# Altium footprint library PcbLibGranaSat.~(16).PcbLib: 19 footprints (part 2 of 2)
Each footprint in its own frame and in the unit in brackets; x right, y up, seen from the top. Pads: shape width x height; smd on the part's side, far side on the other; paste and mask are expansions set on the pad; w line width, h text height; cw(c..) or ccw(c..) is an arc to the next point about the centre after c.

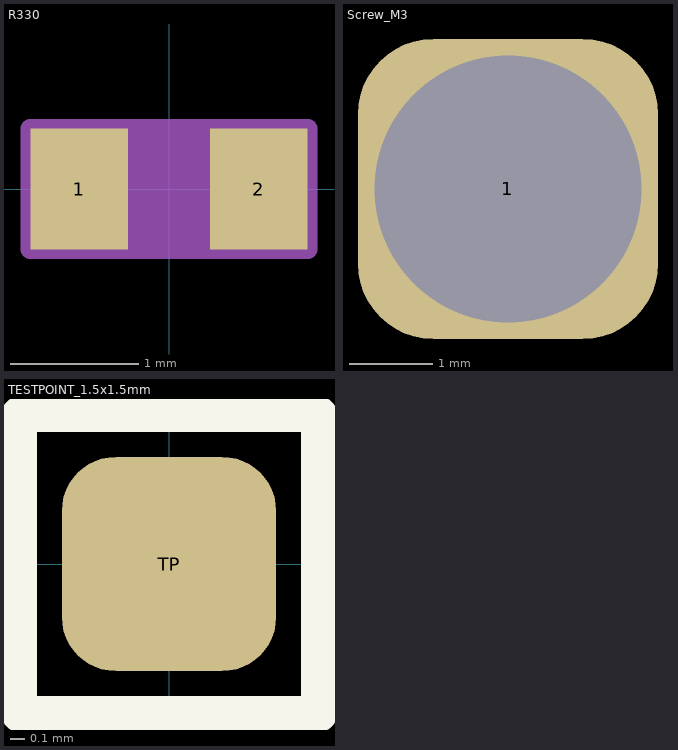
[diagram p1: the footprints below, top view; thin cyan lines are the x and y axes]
## R330 [mil]
pads (2):
  rect 30x37 smd paste+0 mask+0: 1(-27.5,0) 2(27.5,0)
Mechanical 13:
  lines w1: -32.5,-18.5 32.5,-18.5 32.5,18.5 -32.5,18.5 -32.5,-18.5
Mechanical 15:
  region: -32.5,-18.5 -42.5,-18.5 -42.5,18.5 -32.5,18.5 32.5,18.5 42.5,18.5 42.5,-18.5 32.5,-18.5
  lines w6: -42.5,-18.5 -42.5,18.5 -32.5,18.5 32.5,18.5 42.5,18.5 42.5,-18.5 32.5,-18.5 -32.5,-18.5 -42.5,-18.5
3D body: height 10, standoff 0, extent 0,0 10,10

## Screw_M3 [mm] "Main CubeSAT bus M3 screw"
pads (1):
  rrect50% 3.6x3.6 hole 3.2: 1(72.04,27.44)

## TESTPOINT_1.5x1.5mm [mm] "Punto de test de 1.5x1.5mm"
pads (1):
  rrect50% 1.5x1.5 smd: TP(0,0)
Top Overlay:
  lines w0.254: -1.05,-1.05 -1.05,1.05 1.05,1.05 1.05,-1.05 -1.05,-1.05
